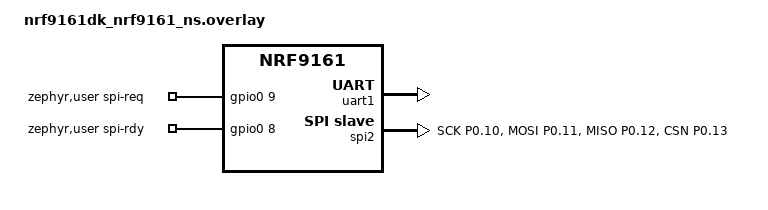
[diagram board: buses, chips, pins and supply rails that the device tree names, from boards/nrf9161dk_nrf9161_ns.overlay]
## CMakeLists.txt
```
#
# Copyright (c) 2024 Nordic Semiconductor
#
# SPDX-License-Identifier: LicenseRef-Nordic-5-Clause
#

cmake_minimum_required(VERSION 3.20.0)

find_package(Zephyr REQUIRED HINTS $ENV{ZEPHYR_BASE})
project(dect_tdma)

file(GLOB app_sources src/*.c)
target_sources(app PRIVATE ${app_sources})
```

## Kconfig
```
#
# Copyright (c) 2024 Nordic Semiconductor
#
# SPDX-License-Identifier: LicenseRef-Nordic-5-Clause
#

menu "TDMA link"

choice
	prompt "TDMA role"
	default TDMA_ROLE_MASTER
	help
	  Which end of the link this image is. The master owns the time base and
	  transmits unconditionally; the slave acquires the master's grid and
	  tracks its clock. Both use the same schedule; only the source of the
	  epoch differs.

config TDMA_ROLE_MASTER
	bool "Master (owns the time base)"

config TDMA_ROLE_SLAVE
	bool "Slave (synchronizes to the master)"

endchoice

endmenu

config CARRIER
	int "Carrier to use"
	default 0
	help
	   The availability of the channels and the exact regulation to use them varies in different countries.
	   See ETSI TS 103 636-2 5.4.2 for the calculation.
	   Band index 1 is set when the carrier is within the range of 525 to 551.
	   This is the only range allowed for band index 1 as other carriers will interfere with other radio devices, including LTE devices.

config NETWORK_ID
	int "Network ID"
	range 1 4294967295
	default 91

config MCS
	int "MCS"
	default 1
	help
	   The MCS impacts how much data can fit into each subslot. prj.conf sets 4.

config TX_POWER
	int "TX power"
	range 0 13
	default 13
	help
	   Transmission power index.
	   See table 6.2.1-3 of ETSI TS 103 636-4 v1.5.1.

menu "Zephyr Kernel"
source "Kconfig.zephyr"
endmenu
```

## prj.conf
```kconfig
# Logging over the VCOM UART
CONFIG_LOG=y
CONFIG_LOG_MODE_DEFERRED=y
CONFIG_SERIAL=y
CONFIG_CONSOLE=y
CONFIG_UART_CONSOLE=y
CONFIG_PRINTK=y
CONFIG_LOG_PRINTK=y
CONFIG_CBPRINTF_FP_SUPPORT=n

# Modem / DECT PHY
CONFIG_NRF_MODEM_LIB=y
CONFIG_NRF_MODEM_LINK_BINARY_DECT_PHY=y
CONFIG_MODEM_ANTENNA=n
CONFIG_MCS=4

# The modem event handler runs on the system workqueue; it must be
# preemptible and below the app threads so TX submission is not delayed
CONFIG_HEAP_MEM_POOL_SIZE=8192
CONFIG_MAIN_STACK_SIZE=4096
CONFIG_SYSTEM_WORKQUEUE_PRIORITY=6
CONFIG_SYSTEM_WORKQUEUE_STACK_SIZE=4096

# SPI slave towards the Teensy, plus the REQ/RDY handshake GPIOs
CONFIG_GPIO=y
CONFIG_SPI=y
CONFIG_SPI_SLAVE=y
CONFIG_SPI_ASYNC=y
CONFIG_POLL=y

CONFIG_TFM_PROFILE_TYPE_MINIMAL=y
CONFIG_HWINFO=y

# Zephyr Logging Puffer deutlich vergrößern
CONFIG_LOG_BUFFER_SIZE=16384
CONFIG_LOG_SPEED=y
```

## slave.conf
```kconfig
# Build the slave image with:
#   west build -b nrf9161dk/nrf9161/ns -- -DEXTRA_CONF_FILE="slave.conf;overlay-eu.conf"
#
# The master is the default and needs no role overlay.

CONFIG_TDMA_ROLE_SLAVE=y

# Larger log buffer so per-packet logging cannot block the modem event handler
CONFIG_LOG_BUFFER_SIZE=16384
```

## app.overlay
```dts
&uart1 {
	status = "okay";
};

&pinctrl {
    spi2_default: spi2_default {
        group1 {
            psels = <
                NRF_PSEL(SPIS_SCK,  0, 10)
                NRF_PSEL(SPIS_MOSI, 0, 11)
                NRF_PSEL(SPIS_MISO, 0, 12)
                NRF_PSEL(SPIS_CSN,  0, 13)
            >;
        };
    };
};

&spi2 {
    compatible = "nordic,nrf-spis";
    status = "okay";
    pinctrl-0 = <&spi2_default>;
    pinctrl-names = "default";
    def-char = <0xFF>;
};

/ {
    aliases {
        drdy-pin = &drdy_out;
        sw0 = &button0;
    };

    outputs {
        compatible = "gpio-leds";
        drdy_out: drdy_out {
            /* Adjust the pin number to whichever nRF pin you are using */
            gpios = <&gpio0 9 GPIO_ACTIVE_HIGH>;
            label = "Data Ready Output Pin";
        };
    };

    /* Falls das Board-Target Buttons nicht standardmäßig aktiviert hat,
    * wird button0 hier explizit auf den P0.08 (oder den DK-spezifischen Pin) gemappt:
    */
    &gpio0 {
        status = "okay";
    };
};
```

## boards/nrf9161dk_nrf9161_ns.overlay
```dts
/*
 * Copyright (c) 2026 Nordic Semiconductor ASA
 *
 * SPDX-License-Identifier: LicenseRef-Nordic-5-Clause
 */

#include <samples/cellular/nrf91_no_bootloader_partitions.dtsi>
#include <zephyr/dt-bindings/pinctrl/nrf-pinctrl.h>

/delete-node/ &sram0_s;
/delete-node/ &sram0_ns;

&sram0 {
	/*
	 * 0x2000_0000  Secure RAM                      (   32 kB)
	 * 0x2000_8000  Non-secure RAM area             (  224 kB)
	 *   0x2000_8000  Modem shared area             ( 23336 B)
	 *     0x2000_8000  control                     (  1832 B)
	 *     0x2000_8728  app -> cell                 (   15 kB)
	 *     0x2000_c328  cell -> app                 (    6 kB)
	 *   0x2000_db28  Application RAM               (206040 B)
	 */
	sram0_s: sram@0 {
		reg = <0x0 0x8000>;
	};

	sram0_ns: sram@8000 {
		reg = <0x8000 0x38000>;
		#address-cells = <1>;
		#size-cells = <1>;
		ranges = <0x0 0x8000 0x38000>;

		/* Must be in first 128 kB of RAM. */
		sram0_ns_modem: sram0_ns@0 {
			/* Modem (shared) memory */
			reg = <0x0 0x5b28>;
			#address-cells = <1>;
			#size-cells = <1>;
			ranges = <0x0 0x0 0x5b28>;

			cpuapp_cpucell_ipc_shm_ctrl: sram0_ns_modem@0 {
				/* Modem IPC control */
				reg = <0x0 0x728>;
			};

			cpuapp_cpucell_ipc_shm_heap: sram0_ns_modem@728 {
				/* Modem IPC transmit */
				reg = <0x728 0x3c00>;
			};

			cpucell_cpuapp_ipc_shm_heap: sram0_ns_modem@4328 {
				/* Modem IPC receive */
				reg = <0x4328 0x1800>;
			};
		};

		sram0_ns_app: sram0_ns@5b28 {
			/* Non-Secure application memory */
			reg = <0x5b28 0x324d8>;
		};
	};
};

&uart1 {
	status = "okay";
};

&pinctrl {
    spi2_default: spi2_default {
        group1 {
            psels = <
                NRF_PSEL(SPIS_SCK,  0, 10)
                NRF_PSEL(SPIS_MOSI, 0, 11)
                NRF_PSEL(SPIS_MISO, 0, 12)
                NRF_PSEL(SPIS_CSN,  0, 13)
            >;
            nordic,drive-mode = <NRF_DRIVE_H0H1>;
        };
    };
};

spi_slave: &spi2 {
    compatible = "nordic,nrf-spis";
    status = "okay";
    pinctrl-0 = <&spi2_default>;
    pinctrl-names = "default";
    def-char = <0xFF>;
};

/ {
    zephyr,user {
        /* Raw outputs for high-speed handshake */
        spi-req-gpios = <&gpio0 9 GPIO_ACTIVE_HIGH>;
        spi-rdy-gpios = <&gpio0 8 GPIO_ACTIVE_HIGH>;
    };
};
```

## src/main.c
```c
#include <zephyr/kernel.h>
#include <zephyr/logging/log.h>

#include "bridge.h"

LOG_MODULE_REGISTER(bridge, LOG_LEVEL_INF);

#define CONFIG_ENABLE_LOGGING 0

/* In main.c oben einfügen (ohne extra .h Datei): */
extern void init_test_button(void);
extern volatile bool tx_suppressed;

/* One pool and queue per direction, see bridge.h. */
K_MEM_SLAB_DEFINE(bridge_frame_slab_dect_tx, sizeof(struct bridge_frame), FRAME_POOL_COUNT, 4);
K_MEM_SLAB_DEFINE(bridge_frame_slab_spi_tx, sizeof(struct bridge_frame), FRAME_POOL_COUNT, 4);
K_MSGQ_DEFINE(bridge_dect_tx_q, sizeof(struct bridge_frame *), FRAME_POOL_COUNT, 4);
K_MSGQ_DEFINE(bridge_spi_tx_q, sizeof(struct bridge_frame *), FRAME_POOL_COUNT, 4);

/* Stats reporter. Runs at the lowest application priority so the log
 * packaging can never delay a time-critical path; main() is not used for this
 * because it runs at priority 0, tied with dect.c's tx_tid.
 */
static void report_thread(void)
{
	while (1)
	{
 		k_sleep(K_SECONDS(5));
		#if IS_ENABLED(CONFIG_ENABLE_LOGGING)
		LOG_INF("-----");
		dect_log_stats();
		LOG_INF("-----");
		spi_bridge_log_stats();
		#endif
	}
}

K_THREAD_DEFINE(report_tid, 2048, report_thread, NULL, NULL, NULL,
				K_LOWEST_APPLICATION_THREAD_PRIO, 0, 0);

int main(void)
{
	int err;

	LOG_INF("bridge starting: 2x %u frames of %u B (%u B total pool)",
			FRAME_POOL_COUNT, (unsigned)sizeof(struct bridge_frame),
			(unsigned)(2 * FRAME_POOL_COUNT * sizeof(struct bridge_frame)));

	/* SPI first: it configures the handshake GPIOs its thread waits for. */
	err = spi_bridge_init();
	if (err)
	{
		LOG_ERR("SPI init failed, err %d", err);
		return err;
	}

	err = dect_init();
	if (err)
	{
		LOG_ERR("DECT init failed, err %d", err);
		return err;
	}

	#if defined(CONFIG_TDMA_ROLE_MASTER)
		/* Button auf dem Master initialisieren */
		init_test_button();
	#endif

	/* Everything runs in its own threads from here on. */
	return 0;
}
```

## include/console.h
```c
#ifndef CONSOLE_H
#define CONSOLE_H

/* * Define a "Function Pointer" type.
 * This says: a console_callback_t is any function that takes a 'const char *' and returns void.
 */
typedef void (*console_callback_t)(const char *cmd);

/* Public API Functions */
void console_init(void);
void console_set_callback(console_callback_t cb);

#endif /* CONSOLE_H */
```

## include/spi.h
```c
#ifndef SPI_H
#define SPI_H

#include <stdint.h>

#define BUF_SIZE 32

/* Define a callback type for when SPI data arrives.
 * We pass the buffer and its length to main.c
 */
typedef void (*spi_rx_callback_t)(const uint8_t *data, uint32_t len);

void spi_init(void);
void spi_set_callback(spi_rx_callback_t cb);

/* Sends a string message over SPI */
void spi_send(const char *message);

#endif /* SPI_H */
```

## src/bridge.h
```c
#ifndef BRIDGE_H
#define BRIDGE_H

/*
 * bridge.h -- internal glue between spi.c, dect.c and main.c: the buffer
 * layout, the pools, the two queues and each module's entry points.
 * protocol.h is the wire contract shared with the Teensy boards.
 *
 * Data flow, one direction (both boards run both):
 *
 *   Teensy A --SPI--> spi.c --bridge_dect_tx_q--> dect.c --air-->
 *   --air--> dect.c --bridge_spi_tx_q--> spi.c --SPI--> Teensy B
 */

#include <stdint.h>
#include <stddef.h>
#include <zephyr/kernel.h>

#include "protocol.h"

/* Largest Ethernet frame the Teensy can hand us (802.1Q tagged, no FCS). */
#define ETH_MAX_PAYLOAD 1522

/* Frames in flight anywhere in the bridge. */
#define FRAME_POOL_COUNT 16

/*
 * The one buffer layout used everywhere.
 *
 *   offset  0 : nrf_tx_rx_header                       30 B
 *               +0  union { cycle, tx_start_lo }             <- written by dect.c on TX
 *                         { dect_rx_ns, nrf_spi_tx_ns }      <- dect_rx_ns set on RX
 *               +8  nrf_spi_rx_ns
 *               +12 dect_tx_ns
 *               +16 t_rx                               14 B  <- SPI RX lands here
 *   offset 30 : eth[]                                        <- payload continues here
 *
 * Because t_rx is the last member of nrf_tx_rx_header, one SPI read of
 * sizeof(t_rx_header) + eth_len bytes starting at &frame->hdr.t_rx fills the
 * Teensy's header and the Ethernet payload in a single transfer, with the
 * locally owned timestamp words already in front of it. On the far side the
 * same buffer goes out over SPI verbatim from offset 0. The asserts below keep
 * this layout safe against edits to protocol.h.
 */
struct bridge_frame
{
	nrf_tx_rx_header hdr;
	uint8_t eth[ETH_MAX_PAYLOAD];
} __packed;

BUILD_ASSERT(sizeof(t_rx_header) == 14, "t_rx_header changed size");
BUILD_ASSERT(sizeof(nrf_tx_rx_header) == 30, "nrf_tx_rx_header changed size");
BUILD_ASSERT(sizeof(t_tx_header) == 38, "t_tx_header changed size");
BUILD_ASSERT(offsetof(nrf_tx_rx_header, t_rx) + sizeof(t_rx_header) ==
				 sizeof(nrf_tx_rx_header),
			 "t_rx must stay last in nrf_tx_rx_header: the SPI RX writes in place");
BUILD_ASSERT(offsetof(struct bridge_frame, eth) == sizeof(nrf_tx_rx_header),
			 "eth[] must follow t_rx with no padding");
BUILD_ASSERT(sizeof(struct bridge_frame) % 4 == 0,
			 "slab block size must be a multiple of the slab alignment");

/* Bytes on the SPI wire in one data phase, per direction, excluding payload. */
#define SPI_RX_HDR_BYTES ((uint16_t)sizeof(t_rx_header))	  /* Teensy A -> nRF */
#define SPI_TX_HDR_BYTES ((uint16_t)sizeof(nrf_tx_rx_header)) /* nRF -> Teensy B */

/* Defined in main.c. One pool per direction rather than a shared one, so
 * frames stuck in one queue (e.g. bridge_spi_tx_q behind a slow Teensy) can
 * never starve the other direction's allocations.
 */
extern struct k_mem_slab bridge_frame_slab_dect_tx; /* feeds bridge_dect_tx_q */
extern struct k_mem_slab bridge_frame_slab_spi_tx;	/* feeds bridge_spi_tx_q */
extern struct k_msgq bridge_dect_tx_q;				/* SPI RX  -> DECT TX */
extern struct k_msgq bridge_spi_tx_q;				/* DECT RX -> SPI TX */

static inline int bridge_dect_tx_frame_alloc(struct bridge_frame **frame, k_timeout_t timeout)
{
	return k_mem_slab_alloc(&bridge_frame_slab_dect_tx, (void **)frame, timeout);
}

static inline void bridge_dect_tx_frame_free(struct bridge_frame *frame)
{
	k_mem_slab_free(&bridge_frame_slab_dect_tx, (void *)frame);
}

static inline int bridge_spi_tx_frame_alloc(struct bridge_frame **frame, k_timeout_t timeout)
{
	return k_mem_slab_alloc(&bridge_frame_slab_spi_tx, (void **)frame, timeout);
}

static inline void bridge_spi_tx_frame_free(struct bridge_frame *frame)
{
	k_mem_slab_free(&bridge_frame_slab_spi_tx, (void *)frame);
}

/* spi.c */
int spi_bridge_init(void);
void spi_bridge_tx_notify(void); /* a frame is waiting: ask the Teensy for clocks */
void spi_bridge_log_stats(void);

/* dect.c */
int dect_init(void);
void dect_log_stats(void);
/* Converts a k_uptime_ticks() sample into the "ns since PPS edge" frame that
 * dect_tx_ns / dect_rx_ns are expressed in.
 */
uint32_t dect_uptime_to_ns_since_pps(int64_t uptime_ticks);

#endif /* BRIDGE_H */
```

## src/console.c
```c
#include <zephyr/kernel.h>
#include <zephyr/drivers/uart.h>
#include <string.h>
#include "console.h"

#define RX_BUF_SIZE 64
static uint8_t rx_double_buf[2][RX_BUF_SIZE];
static char cmd_buf[RX_BUF_SIZE + 1];

const struct device *uart_dev = DEVICE_DT_GET(DT_CHOSEN(zephyr_console));
K_SEM_DEFINE(uart_rx_sem, 0, 1);

// This variable holds the function main() will pass to us
static console_callback_t user_callback = NULL;

void console_set_callback(console_callback_t cb) {
    user_callback = cb;
}

static void uart_cb(const struct device *dev, struct uart_event *evt, void *user_data) {
    switch (evt->type) {
    case UART_RX_RDY:
        memcpy(cmd_buf, evt->data.rx.buf + evt->data.rx.offset, evt->data.rx.len);
        cmd_buf[evt->data.rx.len] = '\0'; 
        k_sem_give(&uart_rx_sem);
        break;
    case UART_RX_BUF_REQUEST:
        uart_rx_buf_rsp(dev, rx_double_buf[1], RX_BUF_SIZE);
        break;
    case UART_RX_DISABLED:
        uart_rx_enable(dev, rx_double_buf[0], RX_BUF_SIZE, 1000);
        break;
    default:
        break;
    }
}

void console_thread_entry(void *arg1, void *arg2, void *arg3) {
    uart_callback_set(uart_dev, uart_cb, NULL);
    uart_rx_enable(uart_dev, rx_double_buf[0], RX_BUF_SIZE, 1000);
    
    while (1) {
        k_sem_take(&uart_rx_sem, K_FOREVER);
        
        // If main.c has registered a callback, trigger it and pass the string!
        if (user_callback != NULL) {
            user_callback(cmd_buf);
        }
    }
}

// Start the background thread automatically
K_THREAD_DEFINE(console_tid, 1024, console_thread_entry, NULL, NULL, NULL, 8, 0, 0);

// A simple init check you can call from main
void console_init(void) {
    if (!device_is_ready(uart_dev)) {
        printk("Console UART not ready!\n");
    }
}
```

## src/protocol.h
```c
#ifndef PROTOCOL_H
#define PROTOCOL_H

#include <stdint.h>

typedef struct __attribute__((packed))
{
    uint16_t eth_payload_len; // Length of raw Ethernet frame to transmit later
    uint32_t delay_budget_ns; // Max allowed bridge transit time
    uint32_t eth_rx_ns;       // Teensy Eth RX PTP Timestamp
    uint32_t t_spi_tx_ns;     // Teensy SPI TX PTP Timestamp
} t_rx_header;

typedef struct __attribute__((packed))
{
    union // 8-byte in-place mutation block
    {
        struct __attribute__((packed))
        {
            uint32_t cycle;       // nrf dect tx
            uint32_t tx_start_lo; // nrf dect tx
        } dect_sched_header;

        struct __attribute__((packed))
        {
            uint32_t dect_rx_ns;    // nrf dect rx Timestamp
            uint32_t nrf_spi_tx_ns; //  nrf spi tx Timestamp
        } nrf_rx_header;
    };

    uint32_t nrf_spi_rx_ns; // nrf spi rx Timestamp
    uint32_t dect_tx_ns;    // nrf dect tx Timestamp

    t_rx_header t_rx; // 14 bytes inherited from Teensy

} nrf_tx_rx_header;

typedef struct __attribute__((packed))
{
    nrf_tx_rx_header nrf_tx_rx; // Contains all 6 previous timestamps
    uint32_t t_spi_rx_ns;       // Teensy B: SPI RX PTP Timestamp
    uint32_t t_eth_tx_ns;       // Teensy B: Eth TX PTP Timestamp
} t_tx_header;

#endif
```

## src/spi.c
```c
#include <string.h>
#include <zephyr/kernel.h>
#include <zephyr/device.h>
#include <zephyr/drivers/spi.h>
#include <zephyr/drivers/gpio.h>
#include <zephyr/logging/log.h>

#include <hal/nrf_spis.h>

#include "bridge.h"

LOG_MODULE_REGISTER(spi_bridge, LOG_LEVEL_INF);

static const struct device *spi_dev = DEVICE_DT_GET(DT_NODELABEL(spi_slave));

/* Same peripheral as spi_dev. spi_xfer() reads SEMSTAT (semaphore ownership),
 * which the Zephyr/nrfx SPIS driver does not expose. It is read-only, so this
 * does not race the driver.
 */
#define SPIS_REG ((NRF_SPIS_Type *)DT_REG_ADDR(DT_NODELABEL(spi_slave)))

static const struct spi_config spi_cfg = {
	.operation = SPI_WORD_SET(8) | SPI_TRANSFER_MSB | SPI_OP_MODE_SLAVE,
	.frequency = 0,
	.cs = {.delay = 0},
};

static const struct gpio_dt_spec req_pin = GPIO_DT_SPEC_GET(DT_PATH(zephyr_user), spi_req_gpios);
static const struct gpio_dt_spec rdy_pin = GPIO_DT_SPEC_GET(DT_PATH(zephyr_user), spi_rdy_gpios);

/* Released by spi_bridge_init() once the GPIOs and SPI device are ready. */
K_SEM_DEFINE(spi_start_sem, 0, 1);

static struct k_poll_signal spi_done_sig;
static struct k_poll_event spi_done_evt;

static struct
{
	atomic_t rx_frames, tx_frames, rx_bytes, tx_bytes;
	atomic_t len_err, xfer_err, nobuf, qfull, hdr_len_mismatch;
} sstats;

/* Pause between arm-failure retries in spi_xfer(). Arm failures are local
 * and invisible to the Teensy, so this only keeps a persistent fault from
 * hot-looping the thread.
 */
#define SPI_ARM_RETRY_MS 50

/* Upper bound on the SEMSTAT spin in spi_xfer(), in ~1 us iterations. The
 * driver's ACQUIRED ISR normally releases the semaphore within a few
 * microseconds; reaching this cap means that ISR is not running.
 */
#define SPI_ARM_SEM_MAX_SPINS 256

/* ------------------------------------------------------------------------- */

/* Arm a transceive, tell the master it may clock, and wait for completion.
 * Either buffer set may be NULL for a one-directional phase. An arm failure
 * is retried in place (the Teensy is still waiting for RDY); an error on
 * completion is logged but not retried, since the Teensy has already run its
 * side of the phase and redoing it could desync the link.
 */
static void spi_xfer(const struct spi_buf_set *tx, const struct spi_buf_set *rx)
{
	int err;

	for (;;)
	{
		k_poll_signal_reset(&spi_done_sig);
		spi_done_evt.state = K_POLL_STATE_NOT_READY;

		err = spi_transceive_signal(spi_dev, &spi_cfg, tx, rx, &spi_done_sig);
		if (err == 0)
		{
			break;
		}

		atomic_inc(&sstats.xfer_err);
		LOG_ERR("SPI arm failed: %d, retrying in %d ms", err, SPI_ARM_RETRY_MS);
		k_sleep(K_MSEC(SPI_ARM_RETRY_MS));
	}

	/* spi_transceive_signal() returning 0 only means the driver has triggered
	 * the ACQUIRE task. Arming finishes when its ACQUIRED ISR writes the
	 * EasyDMA pointers and triggers RELEASE. A transaction started before that
	 * is ignored (0xff on MISO for the whole frame), so the Teensy would read a
	 * 0xffff length and desync. Hold RDY until the semaphore is no longer the
	 * CPU's (an armed, idle SPIS reads FREE). The spin is capped so a
	 * peripheral whose ISR never runs fails loudly instead of hanging.
	 */
	for (uint32_t spins = 0;
		 nrf_spis_semaphore_status_get(SPIS_REG) == NRF_SPIS_SEMSTAT_CPU;
		 spins++)
	{
		if (spins >= SPI_ARM_SEM_MAX_SPINS)
		{
			atomic_inc(&sstats.xfer_err);
			LOG_ERR("SPIS semaphore still CPU-held ~%u us after arm "
					"(SEMSTAT=%d); raising RDY anyway, the next length "
					"exchange will likely be corrupt",
					spins, (int)nrf_spis_semaphore_status_get(SPIS_REG));
			break;
		}
		k_busy_wait(1);
	}

	gpio_pin_set_dt(&rdy_pin, 1);
	k_poll(&spi_done_evt, 1, K_FOREVER);
	gpio_pin_set_dt(&rdy_pin, 0);

	/* A negative result means the transfer did not happen as asked; it is
	 * not retried, see above.
	 */
	if (spi_done_sig.result < 0)
	{
		atomic_inc(&sstats.xfer_err);
		LOG_ERR("SPI transfer completed with error: %d", spi_done_sig.result);
	}
}

/* A frame has been received into *rx_frame. Hand it on and swap in a fresh
 * buffer. If the pool or the queue is full the frame is dropped and its buffer
 * reused, so the thread always owns a receive buffer and never blocks.
 */
static void handle_rx(struct bridge_frame **rx_frame, uint16_t eth_len, int64_t rx_uptime)
{
	struct bridge_frame *frame = *rx_frame;
	struct bridge_frame *next;

	/* rx_uptime was sampled right after spi_xfer() returned. */
	frame->hdr.nrf_spi_rx_ns = dect_uptime_to_ns_since_pps(rx_uptime);

	if (frame->hdr.t_rx.eth_payload_len != eth_len)
	{
		/* The wire length is what landed in the buffer, so it wins. */
		atomic_inc(&sstats.hdr_len_mismatch);
		frame->hdr.t_rx.eth_payload_len = eth_len;
	}

	atomic_inc(&sstats.rx_frames);
	atomic_add(&sstats.rx_bytes, eth_len);

	if (bridge_dect_tx_frame_alloc(&next, K_NO_WAIT) != 0)
	{
		atomic_inc(&sstats.nobuf);
		return; /* keep the buffer, drop the frame */
	}
	if (k_msgq_put(&bridge_dect_tx_q, &frame, K_NO_WAIT) != 0)
	{
		atomic_inc(&sstats.qfull);
		bridge_dect_tx_frame_free(next);
		return;
	}
	*rx_frame = next;
}

static void spi_slave_thread(void)
{
	struct bridge_frame *rx_frame = NULL;
	struct bridge_frame *tx_frame = NULL;

	uint16_t tx_total = 0;
	uint16_t rx_total = 0;

	struct spi_buf tx_len_buf = {.buf = &tx_total, .len = sizeof(tx_total)};
	struct spi_buf_set tx_len_bufs = {.buffers = &tx_len_buf, .count = 1};
	struct spi_buf rx_len_buf = {.buf = &rx_total, .len = sizeof(rx_total)};
	struct spi_buf_set rx_len_bufs = {.buffers = &rx_len_buf, .count = 1};

	struct spi_buf tx_buf = {0};
	struct spi_buf_set tx_bufs = {.buffers = &tx_buf, .count = 1};
	struct spi_buf rx_buf = {0};
	struct spi_buf_set rx_bufs = {.buffers = &rx_buf, .count = 1};

	k_poll_signal_init(&spi_done_sig);
	k_poll_event_init(&spi_done_evt, K_POLL_TYPE_SIGNAL,
					  K_POLL_MODE_NOTIFY_ONLY, &spi_done_sig);

	k_sem_take(&spi_start_sem, K_FOREVER);

	/* Pre-allocate the first RX buffer. */
	bridge_dect_tx_frame_alloc(&rx_frame, K_FOREVER);

	while (1)
	{
		uint16_t rx_eth = 0;
		bool do_rx = false;

		/* ---- what do we have to send? --------------------------- */
		if (tx_frame == NULL)
		{
			struct bridge_frame *next;

			if (k_msgq_get(&bridge_spi_tx_q, &next, K_NO_WAIT) == 0)
			{
				tx_frame = next;
				gpio_pin_set_dt(&req_pin, 1);
			}
		}

		if (tx_frame != NULL)
		{
			tx_total = SPI_TX_HDR_BYTES +
					   tx_frame->hdr.t_rx.eth_payload_len;
			tx_buf.buf = &tx_frame->hdr;
			tx_buf.len = tx_total;
		}
		else
		{
			tx_total = 0;
		}

		/* ---- phase 1: length exchange --------------------------- */
		rx_total = 0;
		spi_xfer(&tx_len_bufs, &rx_len_bufs);

		/* Nothing on the wire in either direction (the Teensy applies the
		 * same check): retry the length exchange.
		 */
		if (tx_total == 0 && rx_total == 0)
		{
			continue;
		}

		/* ---- phase 2 setup ------------------------------------- */
		if (rx_total != 0)
		{
			if (rx_total < SPI_RX_HDR_BYTES ||
				rx_total > SPI_RX_HDR_BYTES + ETH_MAX_PAYLOAD)
			{
				LOG_WRN("bad RX length %u announced", rx_total);
				atomic_inc(&sstats.len_err);
				/* Phase 2 still runs, but do_rx stays false so the DMA
				 * is not pointed at rx_frame with an untrusted length.
				 */
			}
			else
			{
				rx_eth = rx_total - SPI_RX_HDR_BYTES;

				/* Zero the words this side owns; they are not
				 * on the wire and the slab block is dirty.
				 */
				memset(&rx_frame->hdr, 0,
					   offsetof(nrf_tx_rx_header, t_rx));

				rx_buf.buf = &rx_frame->hdr.t_rx;
				rx_buf.len = rx_total;
				do_rx = true;
			}
		}

		/* ---- phase 2: data exchange ------------------------------ */
		spi_xfer(tx_total ? &tx_bufs : NULL, do_rx ? &rx_bufs : NULL);

		/* Sampled here, not in handle_rx(), so handling time is not
		 * folded into the timestamp.
		 */
		int64_t rx_uptime = k_uptime_ticks();

		if (do_rx)
		{
			handle_rx(&rx_frame, rx_eth, rx_uptime);
		}

		if (tx_frame != NULL)
		{
			atomic_inc(&sstats.tx_frames);
			atomic_add(&sstats.tx_bytes,
					   tx_total - SPI_TX_HDR_BYTES);
			bridge_spi_tx_frame_free(tx_frame);
			tx_frame = NULL;

			/* REQ comes down here only; the dequeue at the top of
			 * the loop re-asserts it if more is waiting.
			 */
			gpio_pin_set_dt(&req_pin, 0);
		}
	}
}

/* Priority 7, the lowest in the app (dect.c: tx_tid 0, scheduler_tid 5, system
 * workqueue 6). DECT TX timing is the tighter constraint, so this thread yields
 * to it. The cost: if this thread is late re-arming, the Teensy's next length
 * field reads as garbage, showing up as "bad RX length" warnings or hdr_mm /
 * len_err growth in spi_bridge_log_stats(). If that happens, raise this
 * priority, at least above the system workqueue.
 */
K_THREAD_DEFINE(spi_tid, 4096, spi_slave_thread, NULL, NULL, NULL, 7, 0, 0);

/* ------------------------------------------------------------------------- */

/* dect.c calls this right after putting a frame on bridge_spi_tx_q, to raise
 * REQ even while the thread is parked in spi_xfer(). The Teensy only clocks
 * in response to REQ or its own data, so without this a frame queued during
 * an idle length exchange would not be announced.
 */
void spi_bridge_tx_notify(void)
{
	gpio_pin_set_dt(&req_pin, 1);
}

int spi_bridge_init(void)
{
	int err;

	if (!device_is_ready(spi_dev))
	{
		LOG_ERR("SPI device not ready");
		return -ENODEV;
	}

	err = gpio_pin_configure_dt(&req_pin, GPIO_OUTPUT_INACTIVE);
	if (err)
	{
		LOG_ERR("REQ pin configure failed, err %d", err);
		return err;
	}

	err = gpio_pin_configure_dt(&rdy_pin, GPIO_OUTPUT_INACTIVE);
	if (err)
	{
		LOG_ERR("RDY pin configure failed, err %d", err);
		return err;
	}

	LOG_INF("SPI slave ready: rx hdr %u B, tx hdr %u B, eth max %u B",
			SPI_RX_HDR_BYTES, SPI_TX_HDR_BYTES, ETH_MAX_PAYLOAD);

	k_sem_give(&spi_start_sem);
	return 0;
}

void spi_bridge_log_stats(void)
{
	uint32_t rxb = (uint32_t)atomic_set(&sstats.rx_bytes, 0);
	uint32_t txb = (uint32_t)atomic_set(&sstats.tx_bytes, 0);

	LOG_INF("  spi: rx %ld frm %u B/s | tx %ld frm %u B/s | "
			"len_err %ld xfer_err %ld nobuf %ld qfull %ld hdr_mm %ld",
			atomic_get(&sstats.rx_frames), rxb,
			atomic_get(&sstats.tx_frames), txb,
			atomic_get(&sstats.len_err), atomic_get(&sstats.xfer_err),
			atomic_get(&sstats.nobuf), atomic_get(&sstats.qfull),
			atomic_get(&sstats.hdr_len_mismatch));
}
```
